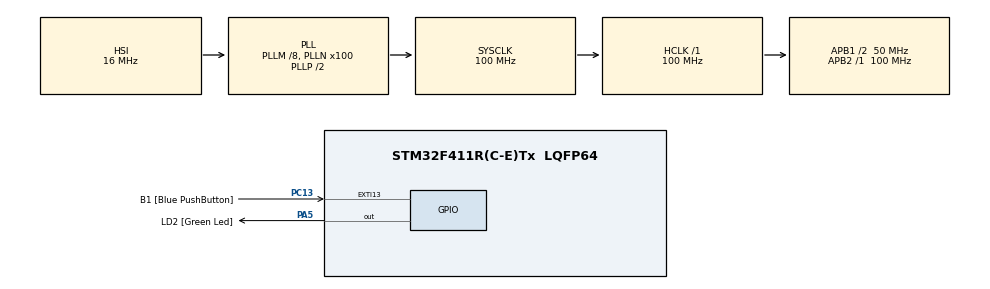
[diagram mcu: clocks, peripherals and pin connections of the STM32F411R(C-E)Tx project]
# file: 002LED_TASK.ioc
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Mcu.Family=STM32F4
Mcu.Name=STM32F411R(C-E)Tx
Mcu.Package=LQFP64
NVIC.PriorityGroup=NVIC_PRIORITYGROUP_4
NVIC.TIM2_IRQn=true\:0\:0\:false\:false\:true\:false\:true\:true
NVIC.TimeBase=TIM2_IRQn
NVIC.TimeBaseIP=TIM2
PA13.GPIO_Label=TMS
PA13.Signal=SYS_JTMS-SWDIO
PA14.GPIO_Label=TCK
PA14.Signal=SYS_JTCK-SWCLK
PA2.GPIO_Label=USART_TX
PA2.Signal=USART2_TX
PA3.GPIO_Label=USART_RX
PA3.Signal=USART2_RX
PA5.GPIO_Label=LD2 [Green Led]
PA5.Signal=GPIO_Output
PB3.GPIO_Label=SWO
PB3.Signal=SYS_JTDO-SWO
PC13-ANTI_TAMP.GPIO_Label=B1 [Blue PushButton]
PC13-ANTI_TAMP.GPIO_ModeDefaultEXTI=GPIO_MODE_IT_FALLING
PC13-ANTI_TAMP.Signal=GPXTI13
PC14-OSC32_IN.Signal=RCC_OSC32_IN
PC15-OSC32_OUT.Signal=RCC_OSC32_OUT
PH0\ -\ OSC_IN.Signal=RCC_OSC_IN
PH1\ -\ OSC_OUT.Signal=RCC_OSC_OUT
ProjectManager.HeapSize=0x200
ProjectManager.StackSize=0x400
ProjectManager.TargetToolchain=STM32CubeIDE
RCC.48MHZClocksFreq_Value=50000000
RCC.AHBFreq_Value=100000000
RCC.APB1CLKDivider=RCC_HCLK_DIV2
RCC.APB1Freq_Value=50000000
RCC.APB1TimFreq_Value=100000000
RCC.APB2Freq_Value=100000000
RCC.APB2TimFreq_Value=100000000
RCC.CortexFreq_Value=100000000
RCC.FLatency-AdvancedSettings=FLASH_LATENCY_3
RCC.HCLKFreq_Value=100000000
RCC.HSE_VALUE=8000000
RCC.HSI_VALUE=16000000
RCC.LSE_VALUE=32768
RCC.PLLM=8
RCC.PLLN=100
RCC.SYSCLKFreq_VALUE=100000000
RCC.SYSCLKSource=RCC_SYSCLKSOURCE_PLLCLK
RCC.VCOOutputFreq_Value=200000000
VP_SYS_VS_tim2.Mode=TIM2
board=NUCLEO-F411RE

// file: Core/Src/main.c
/* USER CODE BEGIN Header */
/**
 ******************************************************************************
 * @file           : main.c
 * @brief          : Main program body
 ******************************************************************************
 * @attention
 *
 * Copyright (c) 2024 STMicroelectronics.
 * All rights reserved.
 *
 * This software is licensed under terms that can be found in the LICENSE file
 * in the root directory of this software component.
 * If no LICENSE file comes with this software, it is provided AS-IS.
 *
 ******************************************************************************
 */
/* USER CODE END Header */
#include "main.h"
#include <stm32f4xx.h>

/* USER CODE BEGIN Includes */
#include "SEGGER_SYSVIEW.h"
#include "FreeRTOS.h"
#include "task.h"
#include <stdio.h>

/* USER CODE END Includes */

/* USER CODE BEGIN PV */

#define DWT_CTRL (*(volatile uint32_t *)0xE0001000)

/* USER CODE END PV */

void SystemClock_Config(void);
static void MX_GPIO_Init(void);
/* USER CODE BEGIN PFP */
void led_red_handler(void *parameters);
void led_orange_handler(void *parameters);
void led_green_handler(void *parameters);
extern void SEGGER_UART_init(uint32_t);

/* USER CODE END PFP */

int main(void)
{
  /* USER CODE BEGIN 1 */

	TaskHandle_t green_handle;
	TaskHandle_t red_handle;
	TaskHandle_t orange_handle;

	BaseType_t status;

  /* USER CODE END 1 */

  /* MCU Configuration--------------------------------------------------------*/

  /* Reset of all peripherals, Initializes the Flash interface and the Systick. */
  HAL_Init();

  /* Configure the system clock */
  SystemClock_Config();

  /* Initialize all configured peripherals */
  MX_GPIO_Init();
  /* USER CODE BEGIN 2 */

	//Enale the CYCNT counter
	DWT_CTRL |= (1 << 0);

	SEGGER_UART_init(500000);

	SEGGER_SYSVIEW_Conf();

	SEGGER_SYSVIEW_Start();

	status = xTaskCreate(led_green_handler, "led_green_handler_task", 200,
			"Hello world form Task-1", 2, &green_handle);

	configASSERT(status == pdPASS);

	status = xTaskCreate(led_red_handler, "led_red_handler_task", 200,
			"Hello world form Task-2", 2, &red_handle);

	configASSERT(status == pdPASS);

	status = xTaskCreate(led_orange_handler, "led_orange_handler_task", 200,
				"Hello world form Task-2", 2, &orange_handle);

		configASSERT(status == pdPASS);

	//start the freeRTOS scheduler
	vTaskStartScheduler();

	//if the control stop here is not enough FreRTOOS heap.

  /* USER CODE END 2 */

  /* Infinite loop */
	while (1) {

	}
}

void SystemClock_Config(void)
{
  RCC_OscInitTypeDef RCC_OscInitStruct = {0};
  RCC_ClkInitTypeDef RCC_ClkInitStruct = {0};

  /** Configure the main internal regulator output voltage
  */
  __HAL_RCC_PWR_CLK_ENABLE();
  __HAL_PWR_VOLTAGESCALING_CONFIG(PWR_REGULATOR_VOLTAGE_SCALE1);

  /** Initializes the RCC Oscillators according to the specified parameters
  * in the RCC_OscInitTypeDef structure.
  */
  RCC_OscInitStruct.OscillatorType = RCC_OSCILLATORTYPE_HSI;
  RCC_OscInitStruct.HSIState = RCC_HSI_ON;
  RCC_OscInitStruct.HSICalibrationValue = RCC_HSICALIBRATION_DEFAULT;
  RCC_OscInitStruct.PLL.PLLState = RCC_PLL_ON;
  RCC_OscInitStruct.PLL.PLLSource = RCC_PLLSOURCE_HSI;
  RCC_OscInitStruct.PLL.PLLM = 8;
  RCC_OscInitStruct.PLL.PLLN = 100;
  RCC_OscInitStruct.PLL.PLLP = RCC_PLLP_DIV2;
  RCC_OscInitStruct.PLL.PLLQ = 4;
  if (HAL_RCC_OscConfig(&RCC_OscInitStruct) != HAL_OK)
  {
    Error_Handler();
  }

  /** Initializes the CPU, AHB and APB buses clocks
  */
  RCC_ClkInitStruct.ClockType = RCC_CLOCKTYPE_HCLK|RCC_CLOCKTYPE_SYSCLK
                              |RCC_CLOCKTYPE_PCLK1|RCC_CLOCKTYPE_PCLK2;
  RCC_ClkInitStruct.SYSCLKSource = RCC_SYSCLKSOURCE_PLLCLK;
  RCC_ClkInitStruct.AHBCLKDivider = RCC_SYSCLK_DIV1;
  RCC_ClkInitStruct.APB1CLKDivider = RCC_HCLK_DIV2;
  RCC_ClkInitStruct.APB2CLKDivider = RCC_HCLK_DIV1;

  if (HAL_RCC_ClockConfig(&RCC_ClkInitStruct, FLASH_LATENCY_3) != HAL_OK)
  {
    Error_Handler();
  }
}

static void MX_GPIO_Init(void)
{
  GPIO_InitTypeDef GPIO_InitStruct = {0};

  /* GPIO Ports Clock Enable */
  __HAL_RCC_GPIOC_CLK_ENABLE();
  __HAL_RCC_GPIOH_CLK_ENABLE();
  __HAL_RCC_GPIOA_CLK_ENABLE();
  __HAL_RCC_GPIOB_CLK_ENABLE();

  /*Configure GPIO pin Output Level */
  HAL_GPIO_WritePin(GPIOA, LD2_Pin|Red_Led_Pin, GPIO_PIN_RESET);

  /*Configure GPIO pin Output Level */
  HAL_GPIO_WritePin(Orange_Led_GPIO_Port, Orange_Led_Pin, GPIO_PIN_RESET);

  /*Configure GPIO pin : B1_Pin */
  GPIO_InitStruct.Pin = B1_Pin;
  GPIO_InitStruct.Mode = GPIO_MODE_IT_FALLING;
  GPIO_InitStruct.Pull = GPIO_NOPULL;
  HAL_GPIO_Init(B1_GPIO_Port, &GPIO_InitStruct);

  /*Configure GPIO pins : USART_TX_Pin USART_RX_Pin */
  GPIO_InitStruct.Pin = USART_TX_Pin|USART_RX_Pin;
  GPIO_InitStruct.Mode = GPIO_MODE_AF_PP;
  GPIO_InitStruct.Pull = GPIO_NOPULL;
  GPIO_InitStruct.Speed = GPIO_SPEED_FREQ_VERY_HIGH;
  GPIO_InitStruct.Alternate = GPIO_AF7_USART2;
  HAL_GPIO_Init(GPIOA, &GPIO_InitStruct);

  /*Configure GPIO pins : LD2_Pin Red_Led_Pin */
  GPIO_InitStruct.Pin = LD2_Pin|Red_Led_Pin;
  GPIO_InitStruct.Mode = GPIO_MODE_OUTPUT_PP;
  GPIO_InitStruct.Pull = GPIO_NOPULL;
  GPIO_InitStruct.Speed = GPIO_SPEED_FREQ_LOW;
  HAL_GPIO_Init(GPIOA, &GPIO_InitStruct);

  /*Configure GPIO pin : Orange_Led_Pin */
  GPIO_InitStruct.Pin = Orange_Led_Pin;
  GPIO_InitStruct.Mode = GPIO_MODE_OUTPUT_PP;
  GPIO_InitStruct.Pull = GPIO_NOPULL;
  GPIO_InitStruct.Speed = GPIO_SPEED_FREQ_LOW;
  HAL_GPIO_Init(Orange_Led_GPIO_Port, &GPIO_InitStruct);

}

/* USER CODE BEGIN 4 */

void led_green_handler(void *parameters) {

	while (1) {
		SEGGER_SYSVIEW_PrintfTarget("Toggling Green");
		HAL_GPIO_TogglePin(GPIOA, LD2_Pin);
		vTaskDelay(pdMS_TO_TICKS(1000));
	}

}

void led_red_handler(void *parameters) {

	while (1) {
		SEGGER_SYSVIEW_PrintfTarget("Toggling red");
		HAL_GPIO_TogglePin(GPIOA, Red_Led_Pin);
		vTaskDelay(pdMS_TO_TICKS(800));
	}

}

void led_orange_handler(void *parameters) {

	while (1) {
		SEGGER_SYSVIEW_PrintfTarget("Toggling Orange");
		HAL_GPIO_TogglePin(GPIOB, Orange_Led_Pin);
		vTaskDelay(pdMS_TO_TICKS(400));
	}

}
/* USER CODE END 4 */

void HAL_TIM_PeriodElapsedCallback(TIM_HandleTypeDef *htim)
{
  if (htim->Instance == TIM3) {
    HAL_IncTick();
  }
}

void Error_Handler(void)
{
	__disable_irq();
	while (1) {
	}
}
